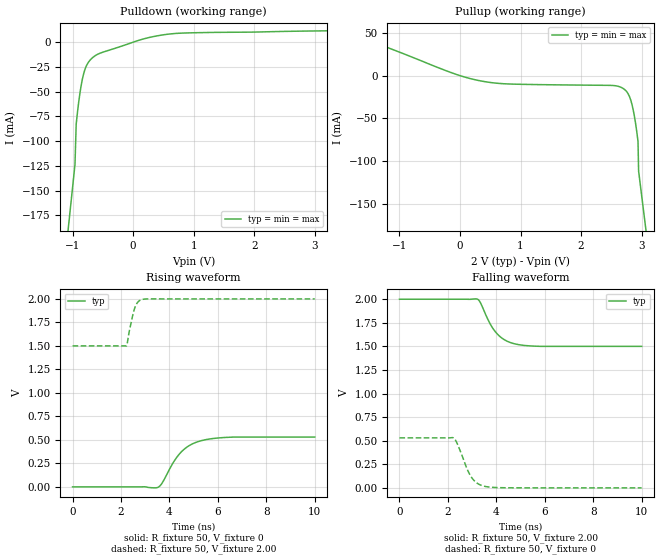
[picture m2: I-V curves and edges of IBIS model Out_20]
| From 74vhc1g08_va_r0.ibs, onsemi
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|//////////////////////////////////////////////////////////////////////////////
|//////////////////////////////////////////////////////////////////////////////
[Model] Out_20
Model_type Output
Polarity Non-Inverting
Vmeas = 1.00
Vref = 2.00
Rref = 1k
Cref = 15pF
|  variable   typ   min   max
C_comp   3.9pF   3.9pF   3.9pF
|//////////////////////////////////////////////////////////////////////////////
[Temperature Range]   25   125   -55
|//////////////////////////////////////////////////////////////////////////////
[Voltage Range]   2.00V   NA   NA
|//////////////////////////////////////////////////////////////////////////////
[Pulldown Reference]   0V   NA   NA
|//////////////////////////////////////////////////////////////////////////////
[Pullup Reference]   2.00V   NA   NA
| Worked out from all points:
|   slope of the pulldown table from 0 to 0.3 V, typ, clamps not added: 57.6 ohm
|   slope of the pullup table from 0 to 0.3 V, typ, clamps not added: 53.7 ohm
|   falling waveform, R_fixture 50, V_fixture 2.00: 20-80 % time 714ps typ, NA min, NA max; typ from 2 V to 1.5 V
|   falling waveform, R_fixture 50, V_fixture 0: 20-80 % time 532ps typ, NA min, NA max; typ from 0.53 V to 0 V
|   rising waveform, R_fixture 50, V_fixture 0: 20-80 % time 888ps typ, NA min, NA max; typ from 0 V to 0.53 V
|   rising waveform, R_fixture 50, V_fixture 2.00: 20-80 % time 260ps typ, NA min, NA max; typ from 1.5 V to 2 V
|//////////////////////////////////////////////////////////////////////////////
[Pulldown]
|   Voltage   I(typ)   I(min)   I(max)
-2V       -736.8mA   -736.8mA   -736.8mA
-1.06V    -181.8mA   -181.8mA   -181.8mA
-960mV    -123.6mA   -123.6mA   -123.6mA
-940mV    -82.79mA   -82.79mA   -82.79mA
-900mV    -61.19mA   -61.19mA   -61.19mA
-860mV    -44.48mA   -44.48mA   -44.48mA
-820mV    -32.6mA    -32.6mA    -32.6mA
-760mV    -22.47mA   -22.47mA   -22.47mA
-600mV    -12.68mA   -12.68mA   -12.68mA
160mV     3.095mA    3.095mA    3.095mA
640mV     8.501mA    8.501mA    8.501mA
4V        11.92mA    11.92mA    11.92mA
|//////////////////////////////////////////////////////////////////////////////
[Pullup]
|   Voltage   I(typ)   I(min)   I(max)
-2V       54.4mA     54.4mA     54.4mA
280mV     -5.296mA   -5.296mA   -5.296mA
760mV     -9.631mA   -9.631mA   -9.631mA
2.5V      -11.45mA   -11.45mA   -11.45mA
2.68V     -14.42mA   -14.42mA   -14.42mA
2.8V      -24.63mA   -24.63mA   -24.63mA
2.84V     -33.54mA   -33.54mA   -33.54mA
2.88V     -47.22mA   -47.22mA   -47.22mA
2.94V     -76.88mA   -76.88mA   -76.88mA
2.95V     -111.7mA   -111.7mA   -111.7mA
3.06V     -174.2mA   -174.2mA   -174.2mA
4V        -708.6mA   -708.6mA   -708.6mA
|//////////////////////////////////////////////////////////////////////////////
|//////////////////////////////////////////////////////////////////////////////
[Ramp]
|  variable   typ   min   max
dV/dt_r   3.180E-01/9.000E-10  NA   NA
dV/dt_f   3.000E-01/7.000E-10  NA   NA
R_load = 50
|//////////////////////////////////////////////////////////////////////////////
[Falling Waveform]
R_fixture = 50
V_fixture = 2.00
C_fixture = 0p
|   time   V(typ)   V(min)   V(max)
0s        2V         NA         NA
3.2ns     2.003V     NA         NA
3.35ns    1.96V      NA         NA
3.7ns     1.761V     NA         NA
4ns       1.643V     NA         NA
4.2ns     1.594V     NA         NA
4.4ns     1.561V     NA         NA
4.9ns     1.519V     NA         NA
5.9ns     1.5V       NA         NA
10ns      1.5V       NA         NA
|//////////////////////////////////////////////////////////////////////////////
[Falling Waveform]
R_fixture = 50
V_fixture = 0
C_fixture = 0p
|   time   V(typ)   V(min)   V(max)
0s        530mV      NA         NA
2.225ns   530.3mV    NA         NA
2.3ns     511.4mV    NA         NA
2.375ns   475.4mV    NA         NA
2.775ns   212.4mV    NA         NA
2.95ns    121.9mV    NA         NA
3.2ns     50.94mV    NA         NA
3.525ns   15.92mV    NA         NA
4.5ns     678.4uV    NA         NA
10ns      0V         NA         NA
|//////////////////////////////////////////////////////////////////////////////
[Rising Waveform]
R_fixture = 50
V_fixture = 0
C_fixture = 0p
|   time   V(typ)   V(min)   V(max)
0s        0V         NA         NA
3.5ns     -7.809mV   NA         NA
3.6ns     8.2mV      NA         NA
3.7ns     41.49mV    NA         NA
4.15ns    255.4mV    NA         NA
4.5ns     374.6mV    NA         NA
4.9ns     450.9mV    NA         NA
5.45ns    499.7mV    NA         NA
6.65ns    529.7mV    NA         NA
10ns      530mV      NA         NA
|//////////////////////////////////////////////////////////////////////////////
[Rising Waveform]
R_fixture = 50
V_fixture = 2.00
C_fixture = 0p
|   time   V(typ)   V(min)   V(max)
0s        1.5V       NA         NA
2.225ns   1.499V     NA         NA
2.25ns    1.513V     NA         NA
2.325ns   1.632V     NA         NA
2.475ns   1.815V     NA         NA
2.575ns   1.908V     NA         NA
2.625ns   1.939V     NA         NA
2.7ns     1.968V     NA         NA
2.9ns     1.996V     NA         NA
10ns      2V         NA         NA
